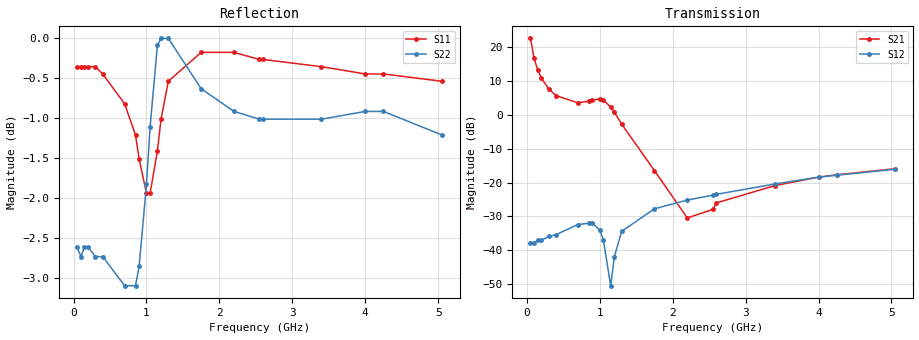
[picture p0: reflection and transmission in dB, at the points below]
!AT-36408
!S-PARAMETERS at Vce=4.8 V  Ic=200 mA.  LAST UPDATED 08-05-96
# ghz s ma r 50
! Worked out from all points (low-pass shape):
!   101 points, 50 MHz to 5.05 GHz, reference 50 ohm
!   highest |S21| = 22.56 dB at 50 MHz (marker M1); lowest = -30.5 dB at 2.2 GHz (marker M2)
!   |S21| within 3 dB of the highest: start of sweep to 75.35 MHz
!   lowest |S11| = -1.9 dB at 1 GHz (marker M3), VSWR 9.00, Z = 5.6 + j4.32 ohm
!   |S11| at or under -10 dB: nowhere
!   |S22| runs from -3.1 to 0.1 dB; largest |S21 - S12| = 13
!   S11 on the Smith chart (normalised r, x): 50 MHz: 0.02, -0.05; 850 MHz: 0.07, +0.10; 2.6 GHz: 0.02, +0.24; 4 GHz: 0.03, +0.43; 5.05 GHz: 0.04, +0.66
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0.05  0.96 -174.0  13.42 93.0  0.013 11.0  0.74 -169.0
0.1  0.96 -178.0  6.79 88.0  0.013 13.0  0.73 -174.0
0.15  0.96 180.0  4.57 85.0  0.014 17.0  0.74 -176.0
0.2  0.96 179.0  3.48 82.0  0.014 20.0  0.74 -177.0
0.3  0.96 177.0  2.41 77.0  0.016 26.0  0.73 -177.0
0.4  0.95 175.0  1.92 72.0  0.017 30.0  0.73 -177.0
0.7  0.91 170.0  1.5 51.0  0.024 29.0  0.7 -173.0
0.85  0.87 168.0  1.59 32.0  0.025 17.0  0.7 -167.0
0.9  0.84 168.0  1.64 24.0  0.025 9.0  0.72 -164.0
1  0.8 170.0  1.71 0.0  0.02 -14.0  0.81 -160.0
1.05  0.8 173.0  1.65 -15.0  0.014 -31.0  0.88 -160.0
1.15  0.85 177.0  1.3 -45.0  0.003 -158.0  0.99 -165.0
1.2  0.89 176.0  1.09 -57.0  0.008 142.0  1 -169.0
1.3  0.94 174.0  0.73 -76.0  0.019 116.0  1 -173.0
1.75  0.98 165.0  0.15 -116.0  0.041 88.0  0.93 -179.0
2.2  0.98 159.0  0.03 179.0  0.055 80.0  0.9 -180.0
2.55  0.97 154.0  0.04 107.0  0.065 77.0  0.89 -180.0
2.6  0.97 153.0  0.05 103.0  0.067 77.0  0.89 180.0
3.4  0.96 142.0  0.09 73.0  0.095 70.0  0.89 178.0
4  0.95 133.0  0.12 63.0  0.12 62.0  0.9 175.0
4.25  0.95 129.0  0.13 59.0  0.128 58.0  0.9 174.0
5.05  0.94 113.0  0.16 47.0  0.157 48.0  0.87 168.0
